VERSION 5.8 ;
DIVIDERCHAR "/" ;
BUSBITCHARS "[]" ;

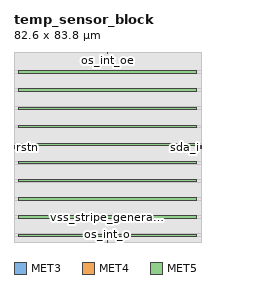
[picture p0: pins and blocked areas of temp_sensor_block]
MACRO temp_sensor_block
  CLASS BLOCK ;
  FOREIGN temp_sensor_block ;
  ORIGIN 0.0 0.0 ;
  SIZE 82.600 BY 83.800 ;
  SYMMETRY X Y ;
  PIN clk
    DIRECTION INPUT ;
    USE SIGNAL ;
    PORT
      LAYER MET3 ;
        RECT 0.000 41.050 0.800 41.150 ;
    END
  END clk
  PIN os_int_o
    DIRECTION OUTPUT ;
    USE SIGNAL ;
    PORT
      LAYER MET4 ;
        RECT 41.250 0.000 41.350 0.800 ;
    END
  END os_int_o
  PIN os_int_oe
    DIRECTION OUTPUT ;
    USE SIGNAL ;
    PORT
      LAYER MET4 ;
        RECT 41.250 83.000 41.350 83.800 ;
    END
  END os_int_oe
  PIN rstn
    DIRECTION INPUT ;
    USE SIGNAL ;
    PORT
      LAYER MET3 ;
        RECT 0.000 41.450 0.800 41.550 ;
    END
  END rstn
  PIN scl_i
    DIRECTION INPUT ;
    USE SIGNAL ;
    PORT
      LAYER MET3 ;
        RECT 0.000 42.250 0.800 42.350 ;
    END
  END scl_i
  PIN sda_i
    DIRECTION INPUT ;
    USE SIGNAL ;
    PORT
      LAYER MET3 ;
        RECT 81.800 41.450 82.600 41.550 ;
    END
  END sda_i
  PIN sda_o
    DIRECTION OUTPUT ;
    USE SIGNAL ;
    PORT
      LAYER MET3 ;
        RECT 81.800 41.850 82.600 41.950 ;
    END
  END sda_o
  PIN sda_oe
    DIRECTION OUTPUT ;
    USE SIGNAL ;
    PORT
      LAYER MET3 ;
        RECT 81.800 42.250 82.600 42.350 ;
    END
  END sda_oe
  PIN t2f_in
    DIRECTION INPUT ;
    USE SIGNAL ;
    PORT
      LAYER MET3 ;
        RECT 0.000 41.850 0.800 41.950 ;
    END
  END t2f_in
  PIN vdd_stripe_generate
    DIRECTION INOUT ;
    USE POWER ;
    PORT
      LAYER MET5 ;
        RECT 2.000 2.500 80.600 3.500 ;
      LAYER MET5 ;
        RECT 2.000 18.500 80.600 19.500 ;
      LAYER MET5 ;
        RECT 2.000 34.500 80.600 35.500 ;
      LAYER MET5 ;
        RECT 2.000 50.500 80.600 51.500 ;
      LAYER MET5 ;
        RECT 2.000 66.500 80.600 67.500 ;
    END
  END vdd_stripe_generate
  PIN vss_stripe_generate
    DIRECTION INOUT ;
    USE GROUND ;
    PORT
      LAYER MET5 ;
        RECT 2.000 10.500 80.600 11.500 ;
      LAYER MET5 ;
        RECT 2.000 26.500 80.600 27.500 ;
      LAYER MET5 ;
        RECT 2.000 42.500 80.600 43.500 ;
      LAYER MET5 ;
        RECT 2.000 58.500 80.600 59.500 ;
      LAYER MET5 ;
        RECT 2.000 74.500 80.600 75.500 ;
    END
  END vss_stripe_generate
  OBS
    LAYER MET1 ;
    RECT 0.000 0.000 82.600 83.800 ;
    LAYER MET2 ;
    RECT 0.000 0.000 82.600 83.800 ;
    LAYER MET3 ;
    RECT 0.000 0.000 82.600 40.950 ;
    LAYER MET3 ;
    RECT 0.900 40.950 82.600 41.250 ;
    LAYER MET3 ;
    RECT 0.000 41.250 82.600 41.350 ;
    LAYER MET3 ;
    RECT 0.900 41.350 81.700 41.650 ;
    LAYER MET3 ;
    RECT 0.000 41.650 82.600 41.750 ;
    LAYER MET3 ;
    RECT 0.900 41.750 81.700 42.050 ;
    LAYER MET3 ;
    RECT 0.000 42.050 82.600 42.150 ;
    LAYER MET3 ;
    RECT 0.900 42.150 81.700 42.450 ;
    LAYER MET3 ;
    RECT 0.000 42.450 82.600 83.800 ;
    LAYER MET4 ;
    RECT 0.000 0.000 41.150 83.800 ;
    LAYER MET4 ;
    RECT 41.150 0.900 41.450 82.900 ;
    LAYER MET4 ;
    RECT 41.450 0.000 82.600 83.800 ;
    LAYER MET5 ;
    RECT 0.000 0.000 82.600 2.400 ;
    LAYER MET5 ;
    RECT 0.000 2.400 1.900 3.600 ;
    LAYER MET5 ;
    RECT 80.700 2.400 82.600 3.600 ;
    LAYER MET5 ;
    RECT 0.000 3.600 82.600 10.400 ;
    LAYER MET5 ;
    RECT 0.000 10.400 1.900 11.600 ;
    LAYER MET5 ;
    RECT 80.700 10.400 82.600 11.600 ;
    LAYER MET5 ;
    RECT 0.000 11.600 82.600 18.400 ;
    LAYER MET5 ;
    RECT 0.000 18.400 1.900 19.600 ;
    LAYER MET5 ;
    RECT 80.700 18.400 82.600 19.600 ;
    LAYER MET5 ;
    RECT 0.000 19.600 82.600 26.400 ;
    LAYER MET5 ;
    RECT 0.000 26.400 1.900 27.600 ;
    LAYER MET5 ;
    RECT 80.700 26.400 82.600 27.600 ;
    LAYER MET5 ;
    RECT 0.000 27.600 82.600 34.400 ;
    LAYER MET5 ;
    RECT 0.000 34.400 1.900 35.600 ;
    LAYER MET5 ;
    RECT 80.700 34.400 82.600 35.600 ;
    LAYER MET5 ;
    RECT 0.000 35.600 82.600 42.400 ;
    LAYER MET5 ;
    RECT 0.000 42.400 1.900 43.600 ;
    LAYER MET5 ;
    RECT 80.700 42.400 82.600 43.600 ;
    LAYER MET5 ;
    RECT 0.000 43.600 82.600 50.400 ;
    LAYER MET5 ;
    RECT 0.000 50.400 1.900 51.600 ;
    LAYER MET5 ;
    RECT 80.700 50.400 82.600 51.600 ;
    LAYER MET5 ;
    RECT 0.000 51.600 82.600 58.400 ;
    LAYER MET5 ;
    RECT 0.000 58.400 1.900 59.600 ;
    LAYER MET5 ;
    RECT 80.700 58.400 82.600 59.600 ;
    LAYER MET5 ;
    RECT 0.000 59.600 82.600 66.400 ;
    LAYER MET5 ;
    RECT 0.000 66.400 1.900 67.600 ;
    LAYER MET5 ;
    RECT 80.700 66.400 82.600 67.600 ;
    LAYER MET5 ;
    RECT 0.000 67.600 82.600 74.400 ;
    LAYER MET5 ;
    RECT 0.000 74.400 1.900 75.600 ;
    LAYER MET5 ;
    RECT 80.700 74.400 82.600 75.600 ;
    LAYER MET5 ;
    RECT 0.000 75.600 82.600 83.800 ;
  END

END temp_sensor_block

END LIBRARY
